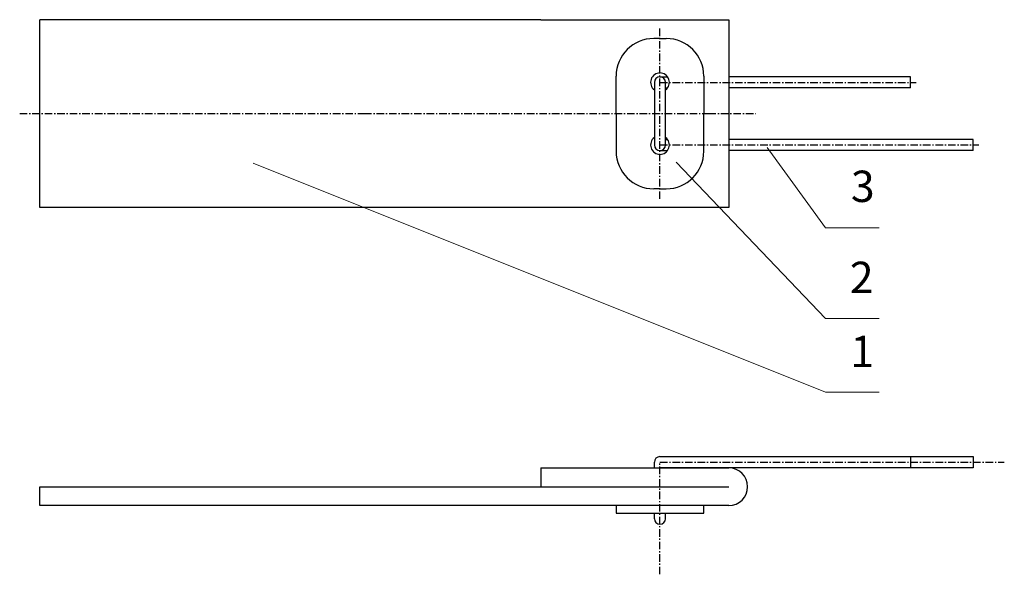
# Model space of a CAD drawing. Units: millimetres. Extents: x -60.1 to 18.5, y 123.9 to 168.2.
import ezdxf

# ---------------------------------------------------------------- set-up
doc = ezdxf.new("R2010")
doc.units = ezdxf.units.MM
doc.header["$LTSCALE"] = 0.2
doc.linetypes.add('ACAD_ISO10W100', pattern=[18, 12, -3, 0, -3])

msp = doc.modelspace()

# ---------------------------------------------------------------- linework, layer by layer
at = {"color": 7, "lineweight": 30, "ltscale": 0.25}
for p, q in [((-18.5, 168.152), (-58.5, 168.152)), ((-58.5, 153.152), (-58.5, 168.152)), ((-18.5, 168.152), (-3.5, 168.152)), ((-3.5, 168.152), (-3.5, 153.152)), ((-9, 166.652), (-9.5, 166.652)), ((-9, 166.652), (-8.5, 166.652)), ((-12.5, 160.652), (-12.5, 163.652)), ((-9, 163.602), (-8.4, 163.602)), ((-5.5, 163.652), (-5.5, 160.652)), ((11, 163.602), (-3.5, 163.602)), ((11, 162.702), (11, 163.602)), ((-9.45, 163.152), (-9.45, 158.152)), ((-8.55, 158.152), (-8.55, 163.152)), ((-8.55, 162.702), (-8.4, 162.702)), ((11, 162.702), (-3.5, 162.702)), ((-12.5, 160.652), (-12.5, 157.652)), ((-5.5, 157.652), (-5.5, 160.652)), ((-8.55, 158.602), (-8.4, 158.602)), ((16, 158.602), (-3.5, 158.602)), ((16, 157.702), (16, 158.602)), ((-9, 157.702), (-8.4, 157.702)), ((16, 157.702), (-3.5, 157.702)), ((-9, 154.652), (-9.5, 154.652)), ((-9, 154.652), (-8.5, 154.652)), ((-18.5, 153.152), (-58.5, 153.152)), ((-3.5, 153.152), (-18.5, 153.152)), ((-9, 133.273), (11, 133.273)), ((11, 133.273), (11, 132.373)), ((11, 133.273), (16, 133.273)), ((16, 133.273), (16, 132.373)), ((-18.5, 132.373), (-3.5, 132.373)), ((-18.5, 132.373), (-18.5, 130.873)), ((-9.45, 132.373), (-9.45, 132.823)), ((11, 132.373), (-9, 132.373)), ((16, 132.373), (11, 132.373)), ((-58.5, 130.873), (-3.5, 130.873)), ((-58.5, 129.373), (-58.5, 130.873)), ((-3.5, 129.373), (-58.5, 129.373)), ((-12.5, 129.373), (-12.5, 128.773)), ((-5.5, 128.773), (-5.5, 129.373)), ((-12.5, 128.773), (-5.5, 128.773)), ((-9.45, 128.323), (-9.45, 128.773)), ((-8.55, 128.323), (-8.55, 128.773))]:
    msp.add_line(p, q, dxfattribs=at)
at = {"color": 1, "linetype": 'ACAD_ISO10W100', "lineweight": 25, "ltscale": 0.25}
for p, q in [((-9, 153.849), (-9, 167.485)), ((-9, 163.152), (11.45, 163.152)), ((-60.12, 160.652), (-32.629, 160.652)), ((-32.629, 160.652), (-5.137, 160.652)), ((-5.137, 160.652), (-1.379, 160.652)), ((-9, 158.152), (16.45, 158.152)), ((-9, 123.883), (-9, 132.823)), ((-9, 132.823), (18.492, 132.823))]:
    msp.add_line(p, q, dxfattribs=at)
at = {"color": 7, "lineweight": 15, "ltscale": 0.25}
for p, q in [((4.204, 151.546), (-0.447, 157.939)), ((4.204, 138.419), (-41.484, 156.699)), ((4.204, 144.308), (-7.695, 156.784)), ((4.204, 151.546), (8.503, 151.546)), ((4.204, 144.308), (8.503, 144.308)), ((8.503, 138.419), (4.204, 138.419))]:
    msp.add_line(p, q, dxfattribs=at)
at = {"color": 7, "lineweight": 30, "ltscale": 0.25}
for centre, radius, start, end in [((-9.5, 163.652), 3, 90, 180), ((-8.5, 163.652), 3, 0, 90), ((-9, 163.152), 0.75, 306.8699, 233.1301), ((-9, 163.152), 0.45, 0, 180), ((-9, 158.152), 0.75, 126.8699, 53.1301), ((-9, 158.152), 0.45, 180, 0), ((-9.5, 157.652), 3, 180, 270), ((-8.5, 157.652), 3, 270, 0), ((-9, 132.823), 0.45, 90, 180), ((-3.5, 130.873), 1.5, 270, 90), ((-9, 128.323), 0.45, 180, 0)]:
    msp.add_arc(centre, radius, start, end, dxfattribs=at)

# ---------------------------------------------------------------- texts
at = {"color": 7, "lineweight": 15, "ltscale": 0.25}
for s, p in [('3', (6.246, 153.602)), ('2', (6.16, 146.335)), ('1', (6.204, 140.419))]:
    msp.add_text(s, height=2.5, dxfattribs=at).set_placement(p)

doc.saveas('drawing.dxf')
